VERSION 5.8 ;
BUSBITCHARS "[]" ;
DIVIDERCHAR "/" ;
CLEARANCEMEASURE EUCLIDEAN ;
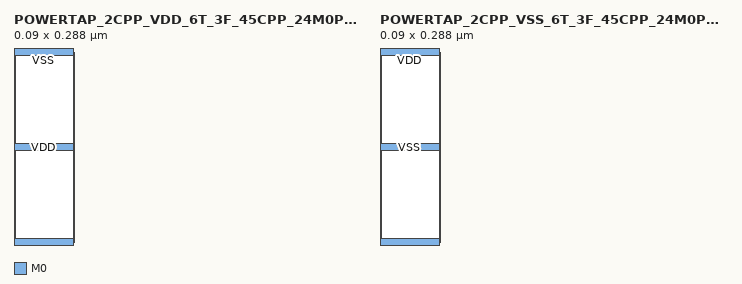
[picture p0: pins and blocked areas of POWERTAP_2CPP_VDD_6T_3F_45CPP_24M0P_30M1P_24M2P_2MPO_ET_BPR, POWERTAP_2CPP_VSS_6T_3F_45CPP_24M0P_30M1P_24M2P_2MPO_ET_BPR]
MACRO POWERTAP_2CPP_VDD_6T_3F_45CPP_24M0P_30M1P_24M2P_2MPO_ET_BPR
  CLASS CORE ;
  ORIGIN 0 0 ;
  FOREIGN POWERTAP_2CPP_VDD_6T_3F_45CPP_24M0P_30M1P_24M2P_2MPO_ET_BPR ;
  SIZE 0.090 BY 0.288 ;
  SYMMETRY X Y ;
  SITE coresite ;
  PIN VSS
    DIRECTION INOUT ;
    USE GROUND ;
    SHAPE ABUTMENT ;
    PORT
      LAYER M0 ;
        RECT 0.000 -0.006 0.090 0.006 ;
        RECT 0.000 0.282 0.090 0.294 ;
    END
  END VSS
  PIN VDD
    DIRECTION INOUT ;
    USE POWER ;
    SHAPE ABUTMENT ;
    PORT
      LAYER M0 ;
        RECT 0.000 0.138 0.090 0.150 ;
    END
  END VDD
END POWERTAP_2CPP_VDD_6T_3F_45CPP_24M0P_30M1P_24M2P_2MPO_ET_BPR

MACRO POWERTAP_2CPP_VSS_6T_3F_45CPP_24M0P_30M1P_24M2P_2MPO_ET_BPR
  CLASS CORE ;
  ORIGIN 0 0 ;
  FOREIGN POWERTAP_2CPP_VSS_6T_3F_45CPP_24M0P_30M1P_24M2P_2MPO_ET_BPR ;
  SIZE 0.090 BY 0.288 ;
  SYMMETRY X Y ;
  SITE coresite ;
  PIN VDD
    DIRECTION INOUT ;
    USE POWER ;
    SHAPE ABUTMENT ;
    PORT
      LAYER M0 ;
        RECT 0.000 -0.006 0.090 0.006 ;
        RECT 0.000 0.282 0.090 0.294 ;
    END
  END VDD
  PIN VSS
    DIRECTION INOUT ;
    USE GROUND ;
    SHAPE ABUTMENT ;
    PORT
      LAYER M0 ;
        RECT 0.000 0.138 0.090 0.150 ;
    END
  END VSS
END POWERTAP_2CPP_VSS_6T_3F_45CPP_24M0P_30M1P_24M2P_2MPO_ET_BPR
